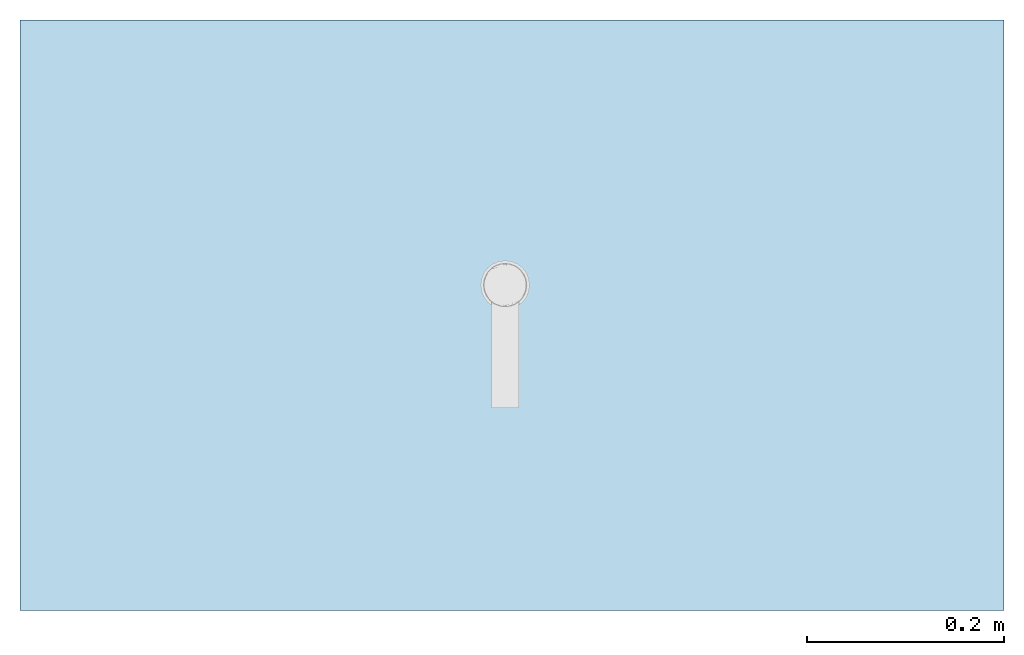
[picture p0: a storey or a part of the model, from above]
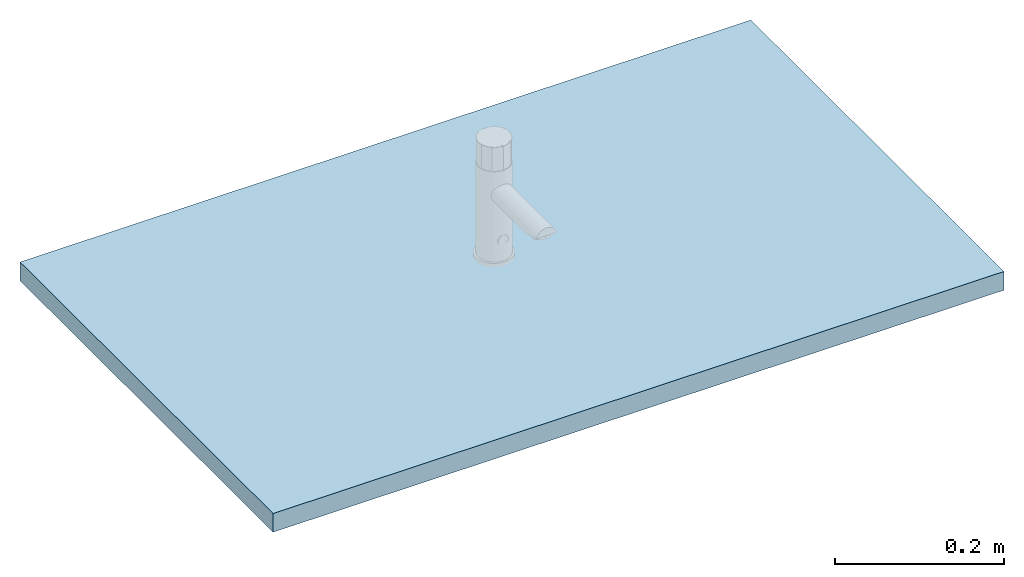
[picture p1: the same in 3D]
Properties of the parts of a building model (IFC2X3)

# File
Description: ViewDefinition [CoordinationView]
Time: 2015-07-20T16:10:34
Written by: The EXPRESS Data Manager Version 5.01.0100.02.64mod : 6 Jun 2012
Made in: 20140709_2115(x64) - Exporter 2014.0.2014.0709 - Default UI
Comment: STEP Physical File produced by: The EXPRESS Data Manager Version 5.01.0100.02.64mod : 6 Jun 2012 * Module: EDMstepFileFactory/EDMstandAlone * Creation date: Mon Jul 20 16:10:34 2015 * Host: BIM-HP * Database: C:\Users\dcole\AppData\Local\Temp\{C8248958-7EF0-4921-9CBC-FD13B6301282}\ifc * Database version: 5507 * Database creation date: Mon Jul 20 16:10:31 2015 * Schema: IFC2X3 * Model: DataRepository.ifc * Model creation date: Mon Jul 20 16:10:32 2015 * Header model: DataRepository.ifc_HeaderModel * Header model creation date: Mon Jul 20 16:10:32 2015 * EDMuser: sdai-user * EDMgroup: sdai-group * License ID and type: 5605 : Permanent license. Expiry date: * EDMstepFileFactory options: 020000

# IfcProject
LongName: C:\Users\dcole\Desktop\Bell_chem\53721_BELL-CHEM\BIM Images 2015\DB100-STL-DB-125-STL.ifc

# IfcSite, Default
RefLatitude: 42, 24, 53, 508911; RefLongitude: -71, -15, -29, -58837; RefElevation: 0 mm

# IfcBuilding
Pset_BuildingCommon - NumberOfStoreys: 1

# IfcBuildingStorey, Level 1
LongName: Level 1; Elevation: 0 mm
Constraints - Elevation Base: Project Base Point; Elevation: 0 mm
Identity Data - Building Story: yes; Name: Level 1; Structural: no
Dimensions - Computation Height: 0 mm
Graphics - Line Weight: 1; Symbol at End 2 Default: yes; Color: 0; Symbol at End 1 Default: no; Line Pattern: -3000010

# IfcBuildingElementProxy: DB100-STL / DB125-STL Dolphin Blue Electronic Infrared Tap, DB100-STL - DB125-STL:DB100-STL / DB125-STL Dolphin Blue Electronic Infrared Tap:3147
In: Level 1
Material: Chrome, Glass
Phasing - Phase Created: New Construction
Constraints - Level: Level: Level 1; Moves With Nearby Elements: no; Host: Floor : Counter; Offset: 0 mm
Dimensions - Volume: 0.000324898 m3; Projection: 135mm; Counter Thickness: Min 2mm - Max 27mm; Width: Ø44 / 50mm; Counter hole: Ø28 - 34mm; Height: 172mm
Pset_ManufacturerTypeInformation - Manufacturer: Bell-Chem Products Co.
Pset_BuildingElementProxyCommon - Reference: DB100-STL / DB125-STL Dolphin Blue Electronic Infrared Tap
Identity Data - Model: DB100-STL / DB125-STL; Tel No.: +44 (0) 1424 202224; Description: Counter Mounted Infrared Tap; Email: info@dolphindispensers.co.uk; URL: www.dolphindispensers.co.uk; Fax No.: +44 (0) 1424 205200; Assembly Description: Misc. Other Plumbing Systems; Address: Southpoint, Compass Park, Bodiam, Robertbridge, TN32 5BS; Assembly Code: D2090900; Manufacturer: Bell-Chem Products Co.
General - Product Data: Touch Free Tap – for ultimate hygiene – prevents cross contamination. Quality polished or brushed chrome plated brass finishes available. Water Supply: Single inlet cold or pre-mixed – a TMV2 or TMV3 thermostatic mixing valve is recommended for premixed applications. Flow rate – as standard 1.0 GPM(US). 0.5 GPM(US) also available to special order along with many other options. If 0.5 GPM(US) flow rate is required specify please specify, in addition to the tap, an upgrade as follows: DB STD Aerator Upgrade to 0.5 GPM(US) spray DBAU001. Interchangeable STD M22/24 Neoperl Aerator insert. Tap settings can be adjusted manually or by using remote control. Mandatory Hygiene Flush feature can be specified to combat Legionella – please specify a time of ordering. WRAS approved product. 2 year manufacturer’s warranty. Max water temperature 70ºC. Operating pressure 0.5–8.0 bar (7–116 PSI). Very low energy usage. We recommend our Dolphin Blue DB61 TMV3 be used in conjunction with this Dolphin Blue tap.; NBS Spec: http://services.ribae.com/nbsproductdata/NBSPlusProduct.aspx?manufacturer=DolphinDispensers&name=Taps%20and%20flush%20valves\Counter%20mounted%20electronic%20taps\DB100-DB125DolphinElectronicTaps.xml&showHeader=False&FromManWS=True&token=5d826ebf20540f991d99fda137868b7c; Product Page Link: http://www.dolphindispensers.co.uk/resources/products/productdetail/000167/db-100-db-125-dolphin-blue-infrared-tap.pdf
Electrical - Power options: Plug-in 9 volt transformer or 9 volt battery (with low battery warning)
Plumbing - Water supply connector: 3/8" BSP

# IfcSlab: Floor:Counter, Floor:Counter:2279
In: Level 1
PredefinedType: FLOOR; Material: <Unnamed> 27 mm
Dimensions - Area: 0.6 m2; Volume: 0.0162 m3; Perimeter: 3200 mm; Thickness: 27 mm
Constraints - Level: Level: Level 1; Height Offset From Level: 0 mm; Related to Mass: no; Room Bounding: yes
Structural - Enable Analytical Model: no; Structural: no
Phasing - Phase Created: New Construction
Pset_SlabCommon - Reference: Counter; IsExternal: no; LoadBearing: yes; PitchAngle: 0 deg
Construction - Default Thickness: 27 mm
Analytical Properties - Absorptance: 0.1; Roughness: 1
Graphics - Coarse Scale Fill Color: 4227327; Coarse Scale Fill Pattern: Solid fill
